VERSION ""

NS_ :

BS_:

BU_: Remote_station Supervisor

BO_ 162 BODY_HEAD_YAW: 4 Supervisor
 SG_ YAW : 16|16@1- (0.1,0) [-180|180] "deg"  Remote_station
 SG_ HEAD : 0|16@1- (0.1,0) [-180|180] "˚"  Remote_station

BO_ 163 BODY_ROLL_PITCH: 4 Supervisor
 SG_ PITCH : 16|16@1- (0.1,0) [-180|180] "deg"  Remote_station
 SG_ ROLL : 0|16@1- (0.1,0) [-180|180] "deg"  Remote_station

BO_ 161 BODY_GPS_ALT: 4 Supervisor
 SG_ ALTITUDE : 0|32@1- (0.001,0) [-2000000|2000000] "m"  Remote_station

BO_ 160 BODY_GPS: 8 Supervisor
 SG_ LONGITUDE : 32|32@1- (1E-007,0) [-180|180] "deg"  Remote_station
 SG_ LATITUDE : 0|32@1- (1E-007,0) [-90|90] "deg"  Remote_station

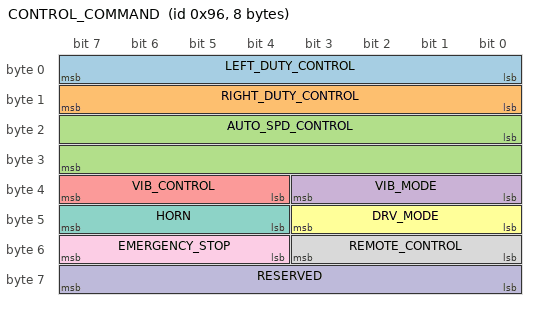
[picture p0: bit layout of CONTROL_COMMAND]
BO_ 150 CONTROL_COMMAND: 8 Remote_station
 SG_ LEFT_DUTY_CONTROL : 0|8@1- (1,0) [0|100] "#"  Supervisor
 SG_ RIGHT_DUTY_CONTROL : 8|8@1- (1,0) [0|100] "#"  Supervisor
 SG_ AUTO_SPD_CONTROL : 16|16@1- (1,0) [-1000|1000] "#"  Supervisor
 SG_ VIB_MODE : 32|4@1+ (1,0) [0|15] "#"  Supervisor
 SG_ VIB_CONTROL : 36|4@1+ (1,0) [0|15] "#"  Supervisor
 SG_ DRV_MODE : 40|4@1+ (1,0) [0|15] "#"  Supervisor
 SG_ HORN : 44|4@1+ (1,0) [0|15] "#"  Supervisor
 SG_ REMOTE_CONTROL : 48|4@1+ (1,0) [0|16] ""  Supervisor
 SG_ EMERGENCY_STOP : 52|4@1+ (1,0) [0|16] ""  Supervisor
 SG_ RESERVED : 56|8@1+ (1,0) [0|65535] "#"  Supervisor

CM_ SG_ 150 VIB_MODE "0: 중립, 1: 저진동, 2: 고진동
";
CM_ SG_ 150 DRV_MODE "0: 거북이, 1:상차, 2:경사전진, 3:경사후진, 4:토끼
";
CM_ SG_ 150 HORN "0: 꺼짐, 1: 켜짐
";
CM_ SG_ 150 REMOTE_CONTROL "0: 꺼짐, 1: 켜짐
";
CM_ SG_ 150 EMERGENCY_STOP "0: 꺼짐, 1: 켜짐
";
BA_DEF_  "BusType" STRING ;
BA_DEF_DEF_  "BusType" "";
BA_ "BusType" "CAN";
